VERSION 5.7 ;
  NOWIREEXTENSIONATPIN ON ;
  DIVIDERCHAR "/" ;
  BUSBITCHARS "[]" ;
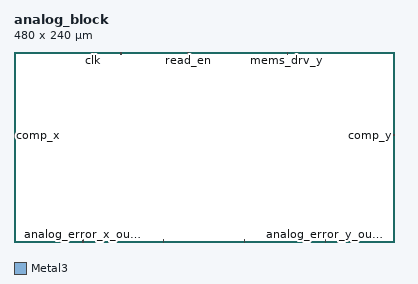
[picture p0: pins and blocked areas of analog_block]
MACRO analog_block
  CLASS BLOCK ;
  FOREIGN analog_block ;
  ORIGIN 0.000 0.000 ;
  SIZE 480.000 BY 240.000 ;

  PIN clk
    DIRECTION INPUT ;
    USE SIGNAL ;
    PORT
      LAYER Metal3 ;
        RECT 100.000 237.000 100.280 240.000 ;
    END
  END clk

  PIN read_en
    DIRECTION INPUT ;
    USE SIGNAL ;
    PORT
      LAYER Metal3 ;
        RECT 219.720 237.000 220.000 240.000 ;
    END
  END read_en

  PIN mems_drv_x
    DIRECTION INPUT ;
    USE SIGNAL ;
    PORT
      LAYER Metal3 ;
        RECT 135.000 237.000 135.280 240.000 ;
    END
  END mems_drv_x

  PIN mems_drv_y
    DIRECTION INPUT ;
    USE SIGNAL ;
    PORT
      LAYER Metal3 ;
        RECT 345.000 237.000 345.280 240.000 ;
    END
  END mems_drv_y

  PIN comp_x
    DIRECTION OUTPUT ;
    USE SIGNAL ;
    PORT
      LAYER Metal3 ;
        RECT 0.000 135.000 0.280 135.280 ;
    END
  END comp_x

  PIN comp_y
    DIRECTION OUTPUT ;
    USE SIGNAL ;
    PORT
      LAYER Metal3 ;
        RECT 479.720 135.000 480.000 135.280 ;
    END
  END comp_y

  PIN analog_error_x_output
    DIRECTION OUTPUT ;
    USE SIGNAL ;
    PORT
      LAYER Metal3 ;
        RECT 87.000 0.000 87.280 3.000 ;
    END
  END analog_error_x_output

  PIN analog_readout_input
    DIRECTION INPUT ;
    USE SIGNAL ;
    PORT
      LAYER Metal3 ;
        RECT 189.000 0.000 189.280 3.000 ;
    END
  END analog_readout_input

  PIN analog_readout_output
    DIRECTION OUTPUT ;
    USE SIGNAL ;
    PORT
      LAYER Metal3 ;
        RECT 291.000 0.000 291.280 3.000 ;
    END
  END analog_readout_output

  PIN analog_error_y_output
    DIRECTION OUTPUT ;
    USE SIGNAL ;
    PORT
      LAYER Metal3 ;
        RECT 393.000 0.000 393.280 3.000 ;
    END
  END analog_error_y_output

END analog_block
END LIBRARY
